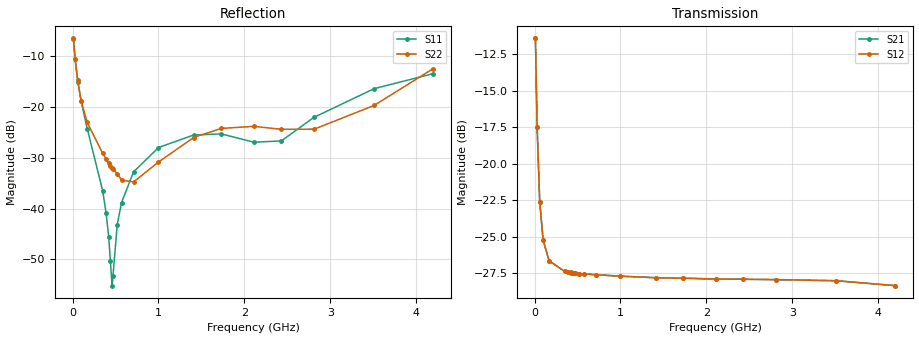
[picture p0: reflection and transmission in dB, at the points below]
! Integrated Device Technology
! Corporate Headquarters
! 6024 Silver Creek Valley Road
! San Jose, CA 95138  USA
! Phone:  1-408-284-8200
! Toll Free:  1-800-223-1366
! Webpage:  http://www.idt.com/
! Timing and RF Division
! 515 Groton Road, Suite 102
! Westford, MA 01886-6024
! Device:  F1950
! Description: 7-bit 0.25 dB Digital Step Attenuator
! Frequency:  150.0 -  4000.00 MHz
! Package:  4x4 mm Thin QFN Plastic Package: 24 pin
! Ports:  2 RF, 12 DC
!  Pin  1  = D0
!  Pin  2  = VDD
!  Pin  3  = Vmode
!  Pin  4  = GND
!  Pin  5  = RF1  =  Port 1
!  Pin  6  = GND
!  Pin  7  = GND
!  Pin  8  = GND
!  Pin  9  = GND
!  Pin 10  = GND
!  Pin 11  = GND
!  Pin 12  = GND
!  Pin 13  = GND
!  Pin 14  = RF2  =  Port 2
!  Pin 15  = GND
!  Pin 16  = LE
!  Pin 17  = CLK
!  Pin 18  = DATE
!  Pin 19  = D6
!  Pin 20  = D5
!  Pin 21  = D4
!  Pin 22  = D3
!  Pin 23  = D2
!  Pin 24  = D1
! State:  107
! Atten State:  26.75 dB
! Voltage:  +5.00 Volts
! Current:  Not Measured mA
! Data:  The device was measured on a the F195X evaluation board which has
!  individual transmission lines to the RF pins.  Data was collected
!  using a calibrated network analyzer.  The evaluation board was
!  de-embedded using a TRL calibration technique.
!  The reference plane is the edge of the package pin.
! Misc:  Board 2019
!  Action Tracker AT0250
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# GHz S dB R 50
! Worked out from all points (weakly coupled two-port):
!   420 points, 10 MHz to 4.2 GHz, reference 50 ohm
!   highest |S21| = -11.41 dB at 10 MHz (marker M1); lowest = -28.3 dB at 4.2 GHz (marker M2)
!   lowest |S11| = -55.2 dB at 460 MHz (marker M3), VSWR 1.00, Z = 49.8 - j0.077 ohm
!   |S11| at or under -10 dB: 26.65 MHz to end of sweep
!   |S22| runs from -35.1 to -6.5 dB; largest |S21 - S12| = 9.6e-05
!   S11 on the Smith chart (normalised r, x): 10 MHz: 2.02, -1.10; 30 MHz: 1.29, -0.64; 60 MHz: 1.11, -0.36; 420 MHz: 1.00, -0.01; 4.2 GHz: 0.68, +0.17
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0.01  -6.61 -27.1  -11.41 -36.1  -11.41 -36.1  -6.52 -28.1
0.03  -10.63 -50.2  -17.51 -55.1  -17.51 -55.1  -10.56 -51.7
0.06  -15.02 -63.3  -22.60 -50.2  -22.60 -50.2  -14.80 -64.9
0.1  -18.89 -70.2  -25.24 -38.4  -25.24 -38.4  -18.87 -70.5
0.17  -24.27 -71.9  -26.64 -26.4  -26.64 -26.4  -23.06 -76.4
0.35  -36.47 -70.3  -27.36 -16.5  -27.36 -16.5  -29.14 -85.4
0.39  -40.87 -72.7  -27.41 -15.7  -27.41 -15.7  -30.24 -87.0
0.42  -45.51 -82.7  -27.44 -15.3  -27.43 -15.3  -31.09 -89.2
0.44  -50.32 -98.2  -27.45 -15.0  -27.45 -15.0  -31.63 -92.2
0.46  -55.18 -153.7  -27.47 -14.8  -27.47 -14.8  -32.04 -95.5
0.47  -53.34 171.1  -27.48 -14.7  -27.48 -14.8  -32.19 -97.2
0.52  -43.18 141.1  -27.51 -14.4  -27.51 -14.4  -33.13 -102.0
0.57  -38.83 135.7  -27.53 -14.2  -27.53 -14.2  -34.40 -111.8
0.71  -32.79 138.3  -27.59 -14.2  -27.59 -14.2  -34.77 -139.8
1  -28.00 148.1  -27.69 -15.5  -27.69 -15.5  -30.85 179.0
1.41  -25.53 163.0  -27.79 -18.2  -27.80 -18.2  -26.03 160.5
1.73  -25.31 168.3  -27.83 -20.5  -27.82 -20.5  -24.24 152.1
2.11  -26.95 158.0  -27.89 -24.1  -27.88 -24.1  -23.83 142.2
2.43  -26.70 126.7  -27.90 -26.6  -27.90 -26.6  -24.41 131.5
2.81  -22.06 105.7  -27.93 -30.3  -27.92 -30.4  -24.40 116.1
3.51  -16.42 117.6  -28.00 -36.7  -28.00 -36.7  -19.72 113.3
4.2  -13.45 145.6  -28.34 -40.7  -28.33 -40.7  -12.45 127.1
